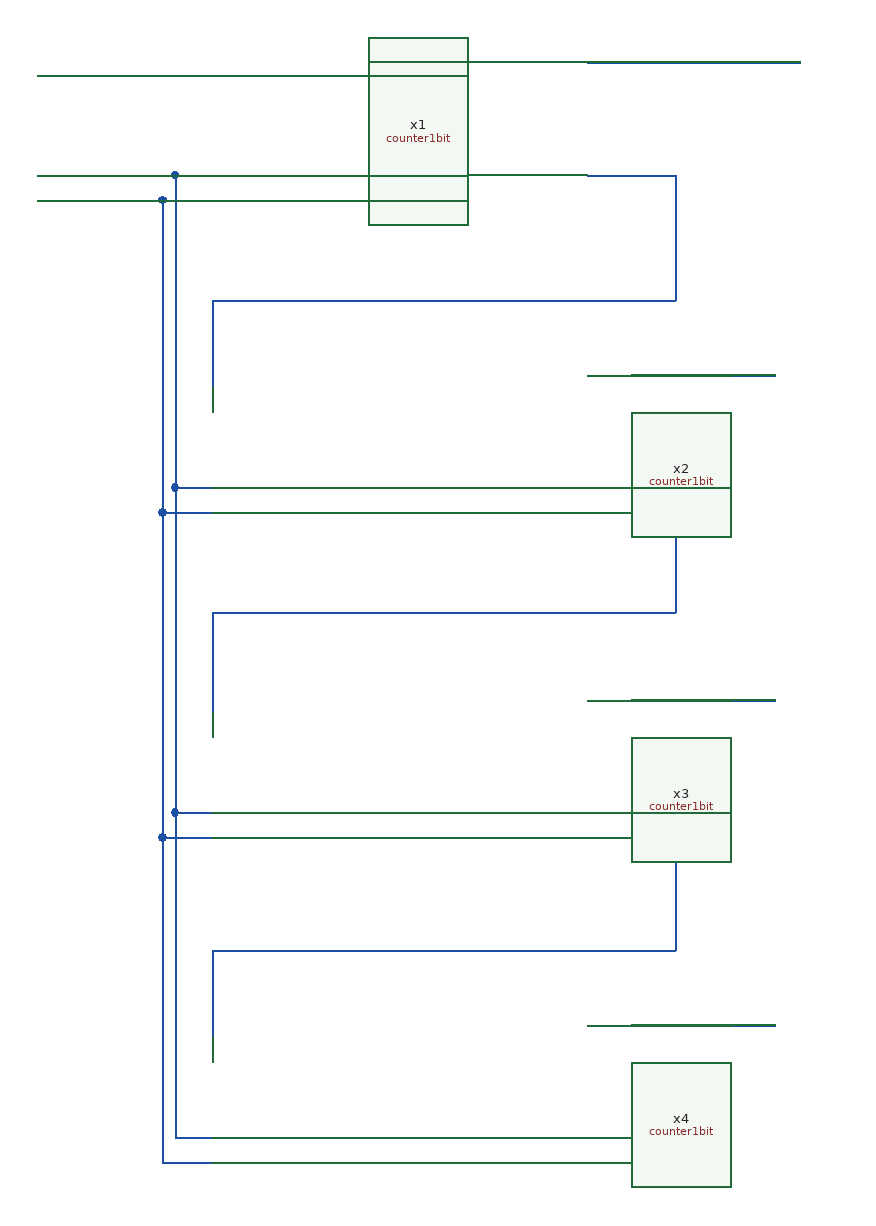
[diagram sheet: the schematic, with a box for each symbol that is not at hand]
v {xschem version=3.4.8RC file_version=1.3}
G {}
K {}
V {}
S {}
F {}
E {}
N 150 -100 220 -100 {lab=#net1}
N 220 -100 220 -0 {lab=#net1}
N -150 0 220 0 {lab=#net1}
N 150 150 220 150 {lab=#net2}
N 220 150 220 250 {lab=#net2}
N -150 250 220 250 {lab=#net2}
N 150 410 220 410 {lab=#net3}
N 220 410 220 520 {lab=#net3}
N 150 580 300 580 {lab=#net4}
N 150 320 300 320 {lab=#net5}
N 150 60 300 60 {lab=#net6}
N 150 -190 320 -190 {lab=#net7}
N -290 -180 -150 -180 {lab=#net8}
N -150 0 -150 70 {lab=#net1}
N -150 250 -150 330 {lab=#net2}
N -150 520 220 520 {lab=#net3}
N -150 520 -150 590 {lab=#net3}
N -190 -80 -150 -80 {lab=#net9}
N -190 -80 -190 170 {lab=#net9}
N -190 170 -150 170 {lab=#net9}
N -190 170 -190 430 {lab=#net9}
N -190 430 -150 430 {lab=#net9}
N -190 430 -190 690 {lab=#net9}
N -190 690 -150 690 {lab=#net9}
N -180 670 -150 670 {lab=#net10}
N -180 410 -180 670 {lab=#net10}
N -180 -100 -150 -100 {lab=#net10}
N -180 150 -150 150 {lab=#net10}
N -180 -100 -180 150 {lab=#net10}
N -180 410 -150 410 {lab=#net10}
N -180 150 -180 410 {lab=#net10}
N -290 -100 -180 -100 {lab=#net10}
N -290 -80 -190 -80 {lab=#net9}
C {blocks/count1bit/schematic/counter1bit.sym} 30 -140 0 0 {name=x1}
C {blocks/count1bit/schematic/counter1bit.sym} 30 110 0 0 {name=x2}
C {blocks/count1bit/schematic/counter1bit.sym} 30 370 0 0 {name=x3}
C {blocks/count1bit/schematic/counter1bit.sym} 30 630 0 0 {name=x4}
